One B-rep face of a CAD part: STEP entity #699684.
In plain terms, the planar face has unit normal (0.656, 0, -0.755).
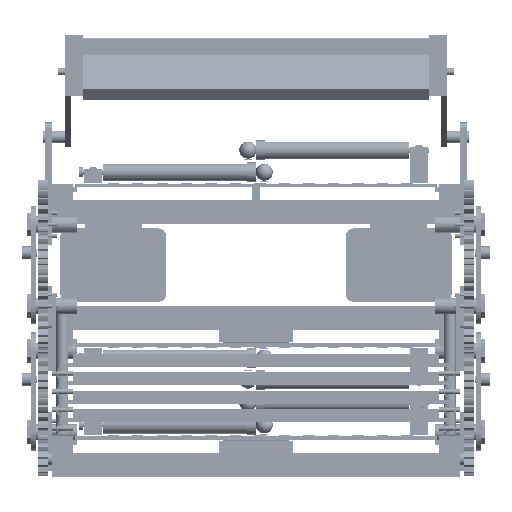
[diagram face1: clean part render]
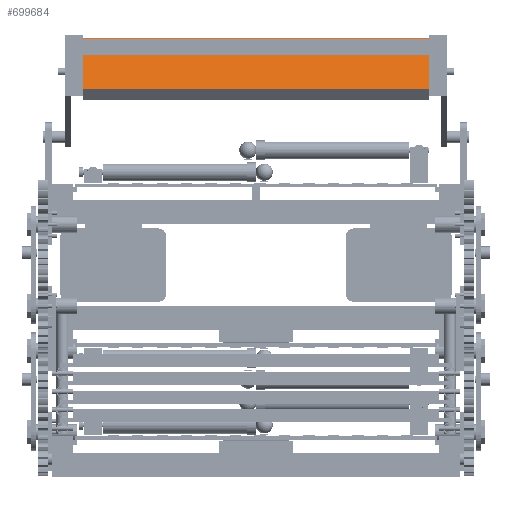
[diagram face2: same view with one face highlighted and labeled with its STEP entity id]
Length unit declared in the file: centimetre
Its self-contained STEP definition (entity closure, numbers rounded to 3 decimals, lengths and spline knots to 4 decimals):
#699375 = VERTEX_POINT('',#699376);
#699376 = CARTESIAN_POINT('',(111.784,-42.5,-24.2804));
#699385 = PLANE('',#699386);
#699386 = AXIS2_PLACEMENT_3D('',#699387,#699388,#699389);
#699387 = CARTESIAN_POINT('',(111.784,-42.5,-24.2804));
#699388 = DIRECTION('',(0.755,0.,0.656));
#699389 = DIRECTION('',(-0.656,0.,0.755));
#699397 = PLANE('',#699398);
#699398 = AXIS2_PLACEMENT_3D('',#699399,#699400,#699401);
#699399 = CARTESIAN_POINT('',(111.784,-42.5,-24.2804));
#699400 = DIRECTION('',(0.,1.,0.));
#699401 = DIRECTION('',(-0.656,0.,0.755));
#699409 = EDGE_CURVE('',#699375,#699410,#699412,.T.);
#699410 = VERTEX_POINT('',#699411);
#699411 = CARTESIAN_POINT('',(111.784,42.5,-24.2804));
#699412 = SURFACE_CURVE('',#699413,(#699417,#699424),.PCURVE_S1.);
#699413 = LINE('',#699414,#699415);
#699414 = CARTESIAN_POINT('',(111.784,-42.5,-24.2804));
#699415 = VECTOR('',#699416,0.1);
#699416 = DIRECTION('',(0.,1.,0.));
#699417 = PCURVE('',#699385,#699418);
#699418 = DEFINITIONAL_REPRESENTATION('',(#699419),#699423);
#699419 = LINE('',#699420,#699421);
#699420 = CARTESIAN_POINT('',(0.,0.));
#699421 = VECTOR('',#699422,1.);
#699422 = DIRECTION('',(0.,-1.));
#699423 = ( GEOMETRIC_REPRESENTATION_CONTEXT(2) 
PARAMETRIC_REPRESENTATION_CONTEXT() REPRESENTATION_CONTEXT('2D SPACE',''
  ) );
#699424 = PCURVE('',#699425,#699430);
#699425 = PLANE('',#699426);
#699426 = AXIS2_PLACEMENT_3D('',#699427,#699428,#699429);
#699427 = CARTESIAN_POINT('',(111.784,-42.5,-24.2804));
#699428 = DIRECTION('',(-0.656,0.,0.755));
#699429 = DIRECTION('',(0.755,0.,0.656));
#699430 = DEFINITIONAL_REPRESENTATION('',(#699431),#699435);
#699431 = LINE('',#699432,#699433);
#699432 = CARTESIAN_POINT('',(0.,0.));
#699433 = VECTOR('',#699434,1.);
#699434 = DIRECTION('',(0.,1.));
#699435 = ( GEOMETRIC_REPRESENTATION_CONTEXT(2) 
PARAMETRIC_REPRESENTATION_CONTEXT() REPRESENTATION_CONTEXT('2D SPACE',''
  ) );
#699453 = PLANE('',#699454);
#699454 = AXIS2_PLACEMENT_3D('',#699455,#699456,#699457);
#699455 = CARTESIAN_POINT('',(111.784,42.5,-24.2804));
#699456 = DIRECTION('',(0.,1.,0.));
#699457 = DIRECTION('',(-0.656,0.,0.755));
#699495 = VERTEX_POINT('',#699496);
#699496 = CARTESIAN_POINT('',(126.1235,-42.5,-11.8153));
#699505 = PLANE('',#699506);
#699506 = AXIS2_PLACEMENT_3D('',#699507,#699508,#699509);
#699507 = CARTESIAN_POINT('',(126.1235,-42.5,-11.8153));
#699508 = DIRECTION('',(0.755,0.,0.656));
#699509 = DIRECTION('',(-0.656,0.,0.755));
#699524 = EDGE_CURVE('',#699495,#699525,#699527,.T.);
#699525 = VERTEX_POINT('',#699526);
#699526 = CARTESIAN_POINT('',(126.1235,42.5,-11.8153));
#699527 = SURFACE_CURVE('',#699528,(#699532,#699539),.PCURVE_S1.);
#699528 = LINE('',#699529,#699530);
#699529 = CARTESIAN_POINT('',(126.1235,-42.5,-11.8153));
#699530 = VECTOR('',#699531,0.1);
#699531 = DIRECTION('',(0.,1.,0.));
#699532 = PCURVE('',#699505,#699533);
#699533 = DEFINITIONAL_REPRESENTATION('',(#699534),#699538);
#699534 = LINE('',#699535,#699536);
#699535 = CARTESIAN_POINT('',(0.,0.));
#699536 = VECTOR('',#699537,1.);
#699537 = DIRECTION('',(0.,-1.));
#699538 = ( GEOMETRIC_REPRESENTATION_CONTEXT(2) 
PARAMETRIC_REPRESENTATION_CONTEXT() REPRESENTATION_CONTEXT('2D SPACE',''
  ) );
#699539 = PCURVE('',#699425,#699540);
#699540 = DEFINITIONAL_REPRESENTATION('',(#699541),#699545);
#699541 = LINE('',#699542,#699543);
#699542 = CARTESIAN_POINT('',(19.,0.));
#699543 = VECTOR('',#699544,1.);
#699544 = DIRECTION('',(0.,1.));
#699545 = ( GEOMETRIC_REPRESENTATION_CONTEXT(2) 
PARAMETRIC_REPRESENTATION_CONTEXT() REPRESENTATION_CONTEXT('2D SPACE',''
  ) );
#699594 = EDGE_CURVE('',#699375,#699495,#699595,.T.);
#699595 = SURFACE_CURVE('',#699596,(#699600,#699607),.PCURVE_S1.);
#699596 = LINE('',#699597,#699598);
#699597 = CARTESIAN_POINT('',(111.784,-42.5,-24.2804));
#699598 = VECTOR('',#699599,0.1);
#699599 = DIRECTION('',(0.755,0.,0.656));
#699600 = PCURVE('',#699397,#699601);
#699601 = DEFINITIONAL_REPRESENTATION('',(#699602),#699606);
#699602 = LINE('',#699603,#699604);
#699603 = CARTESIAN_POINT('',(0.,0.));
#699604 = VECTOR('',#699605,1.);
#699605 = DIRECTION('',(0.,1.));
#699606 = ( GEOMETRIC_REPRESENTATION_CONTEXT(2) 
PARAMETRIC_REPRESENTATION_CONTEXT() REPRESENTATION_CONTEXT('2D SPACE',''
  ) );
#699607 = PCURVE('',#699425,#699608);
#699608 = DEFINITIONAL_REPRESENTATION('',(#699609),#699613);
#699609 = LINE('',#699610,#699611);
#699610 = CARTESIAN_POINT('',(0.,0.));
#699611 = VECTOR('',#699612,1.);
#699612 = DIRECTION('',(1.,0.));
#699613 = ( GEOMETRIC_REPRESENTATION_CONTEXT(2) 
PARAMETRIC_REPRESENTATION_CONTEXT() REPRESENTATION_CONTEXT('2D SPACE',''
  ) );
#699641 = EDGE_CURVE('',#699410,#699525,#699642,.T.);
#699642 = SURFACE_CURVE('',#699643,(#699647,#699654),.PCURVE_S1.);
#699643 = LINE('',#699644,#699645);
#699644 = CARTESIAN_POINT('',(111.784,42.5,-24.2804));
#699645 = VECTOR('',#699646,0.1);
#699646 = DIRECTION('',(0.755,0.,0.656));
#699647 = PCURVE('',#699453,#699648);
#699648 = DEFINITIONAL_REPRESENTATION('',(#699649),#699653);
#699649 = LINE('',#699650,#699651);
#699650 = CARTESIAN_POINT('',(0.,0.));
#699651 = VECTOR('',#699652,1.);
#699652 = DIRECTION('',(0.,1.));
#699653 = ( GEOMETRIC_REPRESENTATION_CONTEXT(2) 
PARAMETRIC_REPRESENTATION_CONTEXT() REPRESENTATION_CONTEXT('2D SPACE',''
  ) );
#699654 = PCURVE('',#699425,#699655);
#699655 = DEFINITIONAL_REPRESENTATION('',(#699656),#699660);
#699656 = LINE('',#699657,#699658);
#699657 = CARTESIAN_POINT('',(0.,85.));
#699658 = VECTOR('',#699659,1.);
#699659 = DIRECTION('',(1.,0.));
#699660 = ( GEOMETRIC_REPRESENTATION_CONTEXT(2) 
PARAMETRIC_REPRESENTATION_CONTEXT() REPRESENTATION_CONTEXT('2D SPACE',''
  ) );
#699684 = ADVANCED_FACE('',(#699685),#699425,.F.);
#699685 = FACE_BOUND('',#699686,.F.);
#699686 = EDGE_LOOP('',(#699687,#699688,#699689,#699690));
#699687 = ORIENTED_EDGE('',*,*,#699409,.F.);
#699688 = ORIENTED_EDGE('',*,*,#699594,.T.);
#699689 = ORIENTED_EDGE('',*,*,#699524,.T.);
#699690 = ORIENTED_EDGE('',*,*,#699641,.F.);
